One B-rep face of a CAD part: STEP entity #1917.
In plain terms, the planar face has unit normal (1, 0, 0).
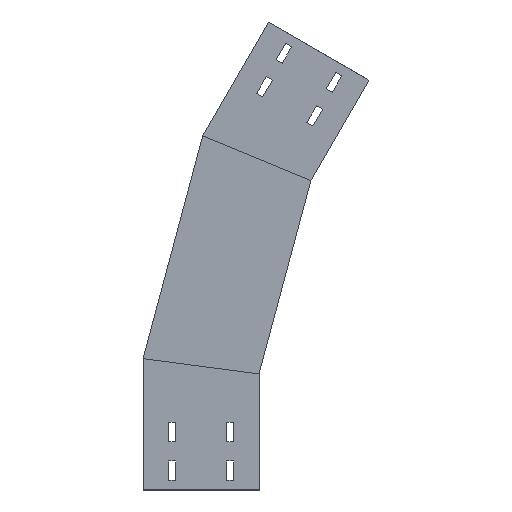
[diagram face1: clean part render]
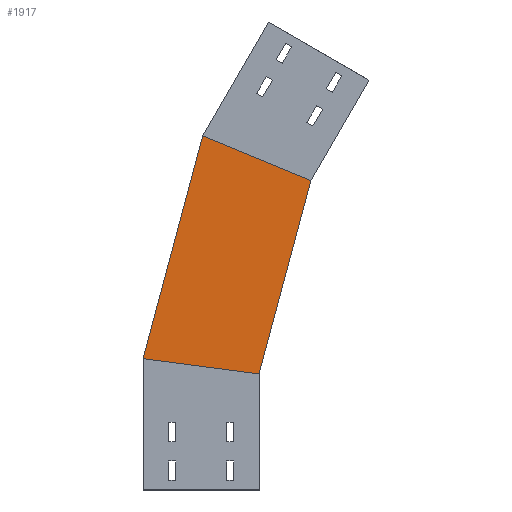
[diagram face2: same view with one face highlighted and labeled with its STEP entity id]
Its self-contained STEP definition (entity closure, numbers rounded to 3 decimals):
#28 = DIRECTION ( 'NONE',  ( 0., -0.991, -0.131 ) ) ;
#40 = VERTEX_POINT ( 'NONE', #1247 ) ;
#80 = EDGE_CURVE ( 'NONE', #1870, #143, #950, .T. ) ;
#112 = CARTESIAN_POINT ( 'NONE',  ( 0., -67.034, 400.175 ) ) ;
#121 = PLANE ( 'NONE',  #996 ) ;
#124 = ORIENTED_EDGE ( 'NONE', *, *, #1473, .T. ) ;
#143 = VERTEX_POINT ( 'NONE', #345 ) ;
#181 = CARTESIAN_POINT ( 'NONE',  ( 0., -19.411, 147.444 ) ) ;
#200 = VECTOR ( 'NONE', #1759, 1000. ) ;
#302 = LINE ( 'NONE', #1987, #718 ) ;
#318 = VERTEX_POINT ( 'NONE', #112 ) ;
#345 = CARTESIAN_POINT ( 'NONE',  ( 0., 0., 150. ) ) ;
#373 = ORIENTED_EDGE ( 'NONE', *, *, #1533, .F. ) ;
#438 = CARTESIAN_POINT ( 'NONE',  ( 0., 5.648, 128.921 ) ) ;
#582 = VECTOR ( 'NONE', #1285, 1000. ) ;
#597 = DIRECTION ( 'NONE',  ( 0., 0., -1. ) ) ;
#662 = CARTESIAN_POINT ( 'NONE',  ( 0., 150.537, 167.744 ) ) ;
#718 = VECTOR ( 'NONE', #1973, 1000. ) ;
#735 = ORIENTED_EDGE ( 'NONE', *, *, #80, .F. ) ;
#828 = LINE ( 'NONE', #662, #582 ) ;
#940 = DIRECTION ( 'NONE',  ( 1., 0., 0. ) ) ;
#950 = LINE ( 'NONE', #181, #1356 ) ;
#996 = AXIS2_PLACEMENT_3D ( 'NONE', #438, #940, #597 ) ;
#1150 = CARTESIAN_POINT ( 'NONE',  ( 0., -100.899, 386.148 ) ) ;
#1247 = CARTESIAN_POINT ( 'NONE',  ( 0., 72.744, 458.073 ) ) ;
#1285 = DIRECTION ( 'NONE',  ( 0., -0.259, 0.966 ) ) ;
#1289 = EDGE_CURVE ( 'NONE', #1870, #40, #828, .T. ) ;
#1312 = ORIENTED_EDGE ( 'NONE', *, *, #1289, .T. ) ;
#1356 = VECTOR ( 'NONE', #28, 1000. ) ;
#1390 = FACE_OUTER_BOUND ( 'NONE', #1612, .T. ) ;
#1473 = EDGE_CURVE ( 'NONE', #40, #318, #1633, .T. ) ;
#1533 = EDGE_CURVE ( 'NONE', #143, #318, #302, .T. ) ;
#1612 = EDGE_LOOP ( 'NONE', ( #1312, #124, #373, #735 ) ) ;
#1633 = LINE ( 'NONE', #1150, #200 ) ;
#1759 = DIRECTION ( 'NONE',  ( 0., -0.924, -0.383 ) ) ;
#1870 = VERTEX_POINT ( 'NONE', #1968 ) ;
#1917 = ADVANCED_FACE ( 'NONE', ( #1390 ), #121, .T. ) ;
#1968 = CARTESIAN_POINT ( 'NONE',  ( 0., 150., 169.748 ) ) ;
#1973 = DIRECTION ( 'NONE',  ( 0., -0.259, 0.966 ) ) ;
#1987 = CARTESIAN_POINT ( 'NONE',  ( 0., 5.648, 128.921 ) ) ;
